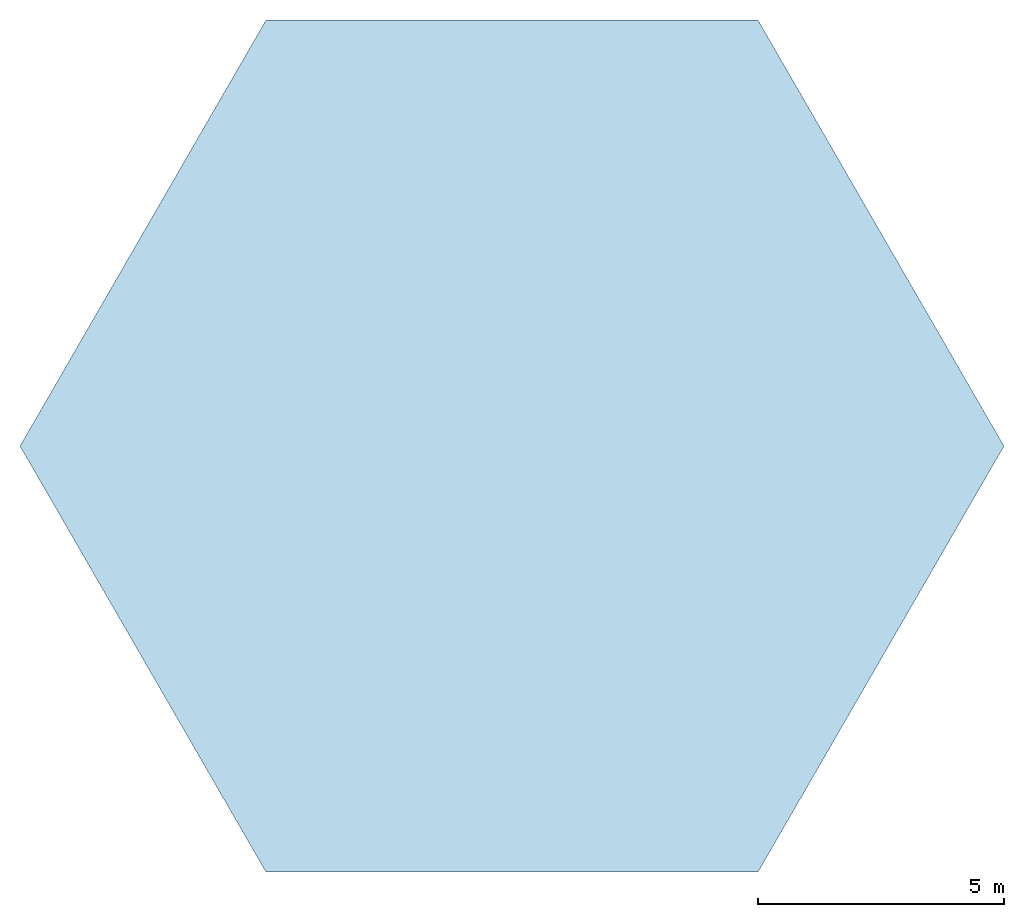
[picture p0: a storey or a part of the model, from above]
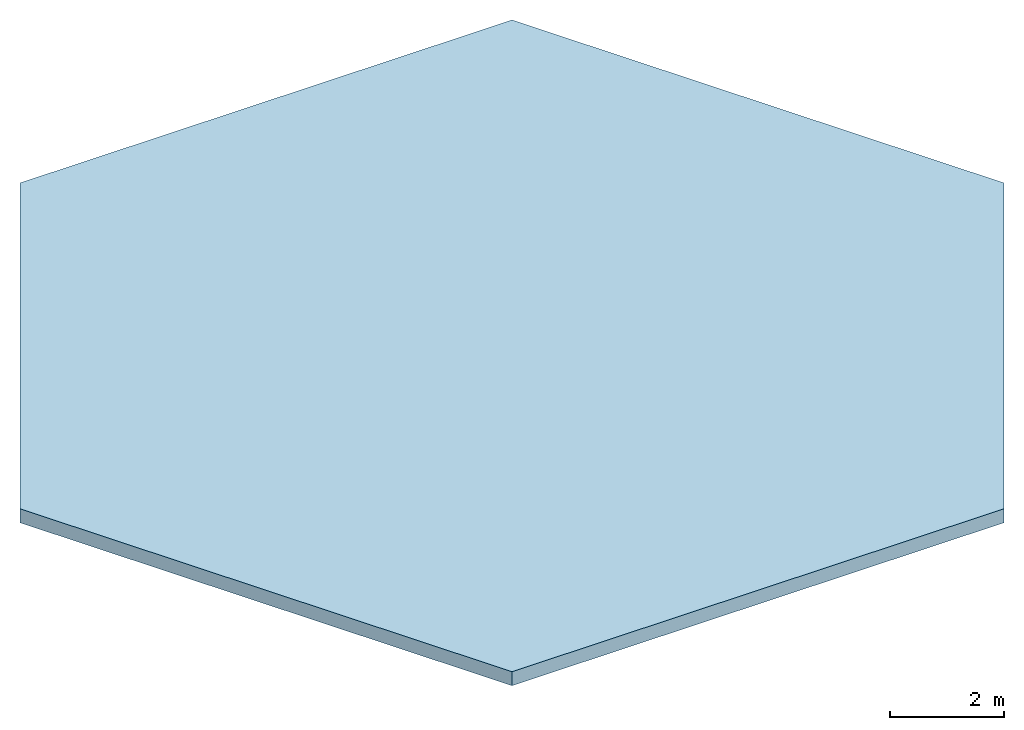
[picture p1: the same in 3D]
Properties of the parts of a building model (IFC4X3_ADD2)

# File
Description: ViewDefinition [ReferenceView_V1.0]
File name: slab-tessellated-unique-vertices.ifc
Time: 2014-07-10T18:45:13
Author: redacted
Organization: redacted
Written by: redacted
Made in: redacted
Comment: use the correct model view definition for the IFC4 reference view
Comment: name
Comment: time_stamp
Comment: author
Comment: organization
Comment: preprocessor_version
Comment: originating_system
Comment: authorization
Comment: set the context of the IFC4 exchange file
Comment: name, units and geometric representation context
Comment: note: IfcOwnerHistory is not in scope of the IFC4 reference view
Comment: optionally define recurring instances, such as zero point and main directions
Comment: those can be referenced multiple times reducing file sizes
Comment: set the representation context for 3D body, and 2D axis representation
Comment: north direction is set to positive y-axis, no geo-spatial coordinates are provided
Comment: set the default units - and the units used for geometric representations
Comment: defines the default building (as required as the minimum spatial element)
Comment: defines the slab as a model element using tessellated geometry
Comment: geometric representation of the slab is given as tessellated geometry
Comment: the list of vertices is collapsed to be unique (minimum exchange data set size)

# IfcProject, P1
Description: project used for the unit test case; LongName: Default project

# IfcBuilding, Grasshopper Building
Description: GH Building; LongName: GH Building

# IfcSlab, Slab 1
In: Grasshopper Building
Description: slab 1 used for the unit test case; PredefinedType: FLOOR
